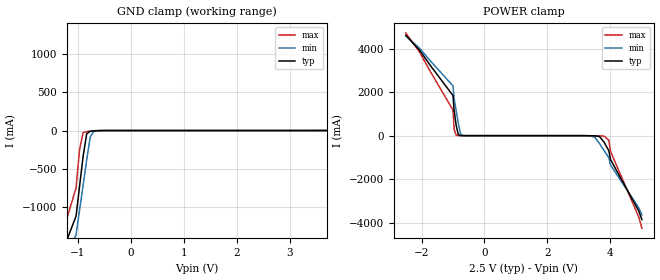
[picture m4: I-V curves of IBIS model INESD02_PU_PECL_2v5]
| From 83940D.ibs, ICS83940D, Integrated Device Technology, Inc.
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[Model] INESD02_PU_PECL_2v5
Model_type   Input
Polarity   Non-Inverting
Vinl = .8V
Vinh =  2V
|   typ   min   max
C_comp   2pF   1.5pF   2.5pF
|   typ   min   max
[Voltage range]  2.5V   2.375V   2.625V
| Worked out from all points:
|   GND clamp passes 1 mA (typ) near -0.59 V on its own axis
|   POWER clamp passes 1 mA (typ) near -0.70 V on its own axis
[GND_clamp]
|Voltage   I(typ)   I(min)   I(max)
-2.5V     -3.894A    -3.674A    -4.294A
-1.25V    -1.521A    -1.7A      -1.261A
-1.031V   -1.125A    -1.372A    -755.3mA
-896.9mV  -335.4mA   -714.7mA   -27.06mA
-695.9mV  -3.401mA   -10.7mA    -6.467mA
3.995V    711.6uA    10.32mA    481.3uA
4.062V    4.029mA    88.04mA    1.401mA
4.129V    40.44mA    547.3mA    3.341mA
4.196V    445.8mA    1.124A     14.79mA
4.263V    1.139A     1.7A       275.9mA
4.5V      1.832A     2.277A     1.163A
5V        3.219A     3.431A     2.937A
[POWER_clamp]
|Voltage   I(typ)   I(min)   I(max)
-2.5V     4.617A     4.594A     4.726A
-1V       1.842A     2.286A     1.176A
-963.9mV  1.149A     1.709A     289.6mA
-896.9mV  456.4mA    1.132A     15.33mA
-829.9mV  42.02mA    556.1mA    3.389mA
-762.9mV  4.159mA    91.01mA    1.421mA
-695.9mV  727.9uA    10.67mA    490.4uA
3.35V     -3.204mA   -9.193mA   -6.2mA
3.8V      -305mA     -689.5mA   -24.7mA
3.95V     -699.9mA   -1.018A    -211mA
4V        -1.095A    -1.346A    -716.4mA
5V        -3.863A    -3.649A    -4.255A
